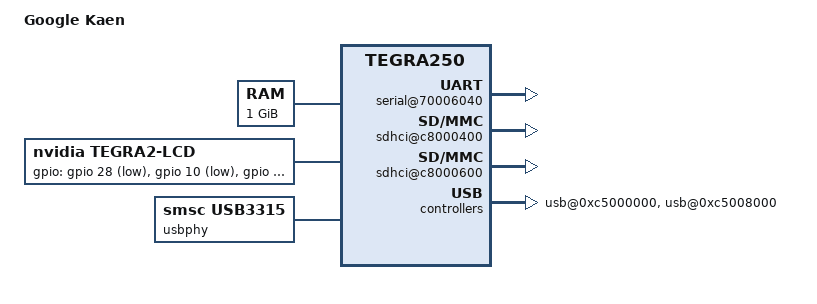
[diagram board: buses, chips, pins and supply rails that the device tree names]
/dts-v1/;

/memreserve/ 0x1c000000 0x04000000;
/include/ "tegra250.dtsi"
/include/ "flashmap-twostop.dtsi"

/ {
	model = "Google Kaen";
	compatible = "google,kaen", "nvidia,tegra250";

	config {
		silent_console = <0>;
		odmdata = <0x300d8011>;
		hwid = "ARM KAEN TEST 3084";
		machine-arch-id = <3217>;

		/* Chrome OS specific GPIO port number */
		gpio_port_write_protect_switch	= <59>;
		gpio_port_recovery_switch	= <56>;
		gpio_port_developer_switch	= <168>;

		/* GPIO polarity: 0=active_low, 1=active_high */
		polarity_write_protect_switch	= <1>;
		polarity_recovery_switch	= <0>;
		polarity_developer_switch	= <1>;
	};

	aliases {
		console = "/serial@70006040";
                usb0 = "/usb@0xc5008000";
                usb1 = "/usb@0xc5000000";

		sdmmc0 = "/sdhci@c8000600";
		sdmmc1 = "/sdhci@c8000400";
	};

	chosen {
		bootargs = "";
	};

	memory {
		device_type = "memory";
		reg = <0x00000000 0x40000000>;
	};

	serial@70006040 {
		status = "ok";
		clock-frequency = <216000000>;
	};

	sdhci@c8000400 {
		status = "ok";
		width = <4>;	/* width of SDIO port */
		removable = <1>;
		/* Parameter 3 bit 0:1=output, 0=input; bit 1:1=high, 0=low */
		cd-gpio = <&gpio 69 0>; /* card detect, gpio PI5 */
		wp-gpio = <&gpio 57 0>; /* write protect, gpio PH1 */
		power-gpio = <&gpio 70 3>; /* power enable, gpio PI6 */
	};

	sdhci@c8000600 {
		status = "ok";
		width = <4>;	/* width of SDIO port */
		removable = <0>;
	};

	lcd {
		compatible = "nvidia,tegra2-lcd";
		width = <1366>;
		height = <768>;
		bits_per_pixel = <16>;
		pwfm = <&pwfm2>;
		display = <&display1>;
		frame-buffer = <0x1C022000>;

		pixel_clock = <62200000>;

		/* Timing: ref_to_sync, sync_width. back_porch, front_porch */
		horiz_timing = <11 58 58 58>;
		vert_timing = <1 4 4 4>;

		/* Parameter 3 bit 0:1=output, 0=input; bit 1:1=high, 0=low */
		gpios = <&gpio 28 3>,	/* backlight PD4 */
			<&gpio 10 3>,	/* lvds shutdown PB2 */
			<&gpio 176 3>,	/* backlight vdd PW0 */
			<&gpio 22 3>;	/* enable vdd pnl PC6 */
	};

	usb@0xc5000000 {
		status = "ok";
		host-mode = <1>;
	};

	usbphy: usbphy@0 {
		compatible = "smsc,usb3315";
		status = "ok";
	};

	usb@0xc5008000 {
		status = "ok";
		utmi = <&usbphy>;
		host-mode = <0>;
	};
	kbc@0x7000e200 {
		keycode-plain    = [00  00  DD  00  DC  00  00  00
				    00  1b  09  '`' 'a' 'z' '1' 'q'
				    00  00  00  00  'd' 'c' '3' 'e'
				    00  00  00  00  00  00  00  00
				    'b' 'g' 't' '5' 'f' 'v' '4' 'r'
				    00  00  00  00  's' 'x' '2' 'w'
				    00  00  ']' 00  'k' ',' '8' 'i'
				    00  00  00  00  00  00  00  00
				    'n' 'h' 'y' '6' 'j' 'm' '7' 'u'
				    00  00  00  00  00  DF  00  DF
				    '=' 5D  '[' '-' ';' '/' '0' 'p'
				    00  00  00  00  'l' '.' '9' 'o'
				    00  00  00  00  00  00  00  00
				    00  00  00  00  00  00  00  00
				    00  08  00  5C  0D  ' ' 00  00
				    00  00  00  00  00  00  00  00];

		keycode-shift	 = [00  00  00  00  00  00  00  00
				    00  1B  09  '~' 'A' 'Z' '!' 'Q'
				    00  00  00  00  'D' 'C' '#' 'E'
				    00  00  00  00  00  00  00  00
				    'B' 'G' 'T' '%' 'F' 'V' '$' 'R'
				    00  00  00  00  'S' 'X' '@' 'W'
				    00  00  '}' 00  'K' '<' '*' 'I'
				    00  00  00  00  00  00  00  00
				    'N' 'H' 'Y' '^' 'J' 'M' '&' 'U'
				    00  00  00  00  00  00  00  00
				    '+' '"' '{' '_' ':' '?' ')' 'P'
				    00  00  00  00  'L' '>' '(' 'O'
				    00  00  00  00  00  00  00  00
				    00  00  00  00  00  00  00  00
				    00  08  00  '|' 0D  ' ' 00  00
				    00  00  00  00  00  00  00  00];

		keycode-ctrl     = [00  00  00  00  00  00  00  00
				    00  00  00  00  01  1a  00  11
				    00  00  00  00  04  03  00  05
				    00  00  00  00  00  00  00  00
				    02  07  14  00  06  16  00  12
				    00  00  00  00  13  18  00  17
				    00  00  00  00  0b  00  00  09
				    00  00  00  00  00  00  00  00
				    0e  08  19  00  0a  0d  00  15
				    00  00  00  00  00  00  00  00
				    00  00  00  00  00  00  00  10
				    00  00  00  00  0c  00  00  0f
				    00  00  00  00  00  00  00  00
				    00  00  00  00  00  00  00  00
				    00  00  00  00  00  00  00  00
				    00  00  00  00  00  00  00  00];
	};
};
